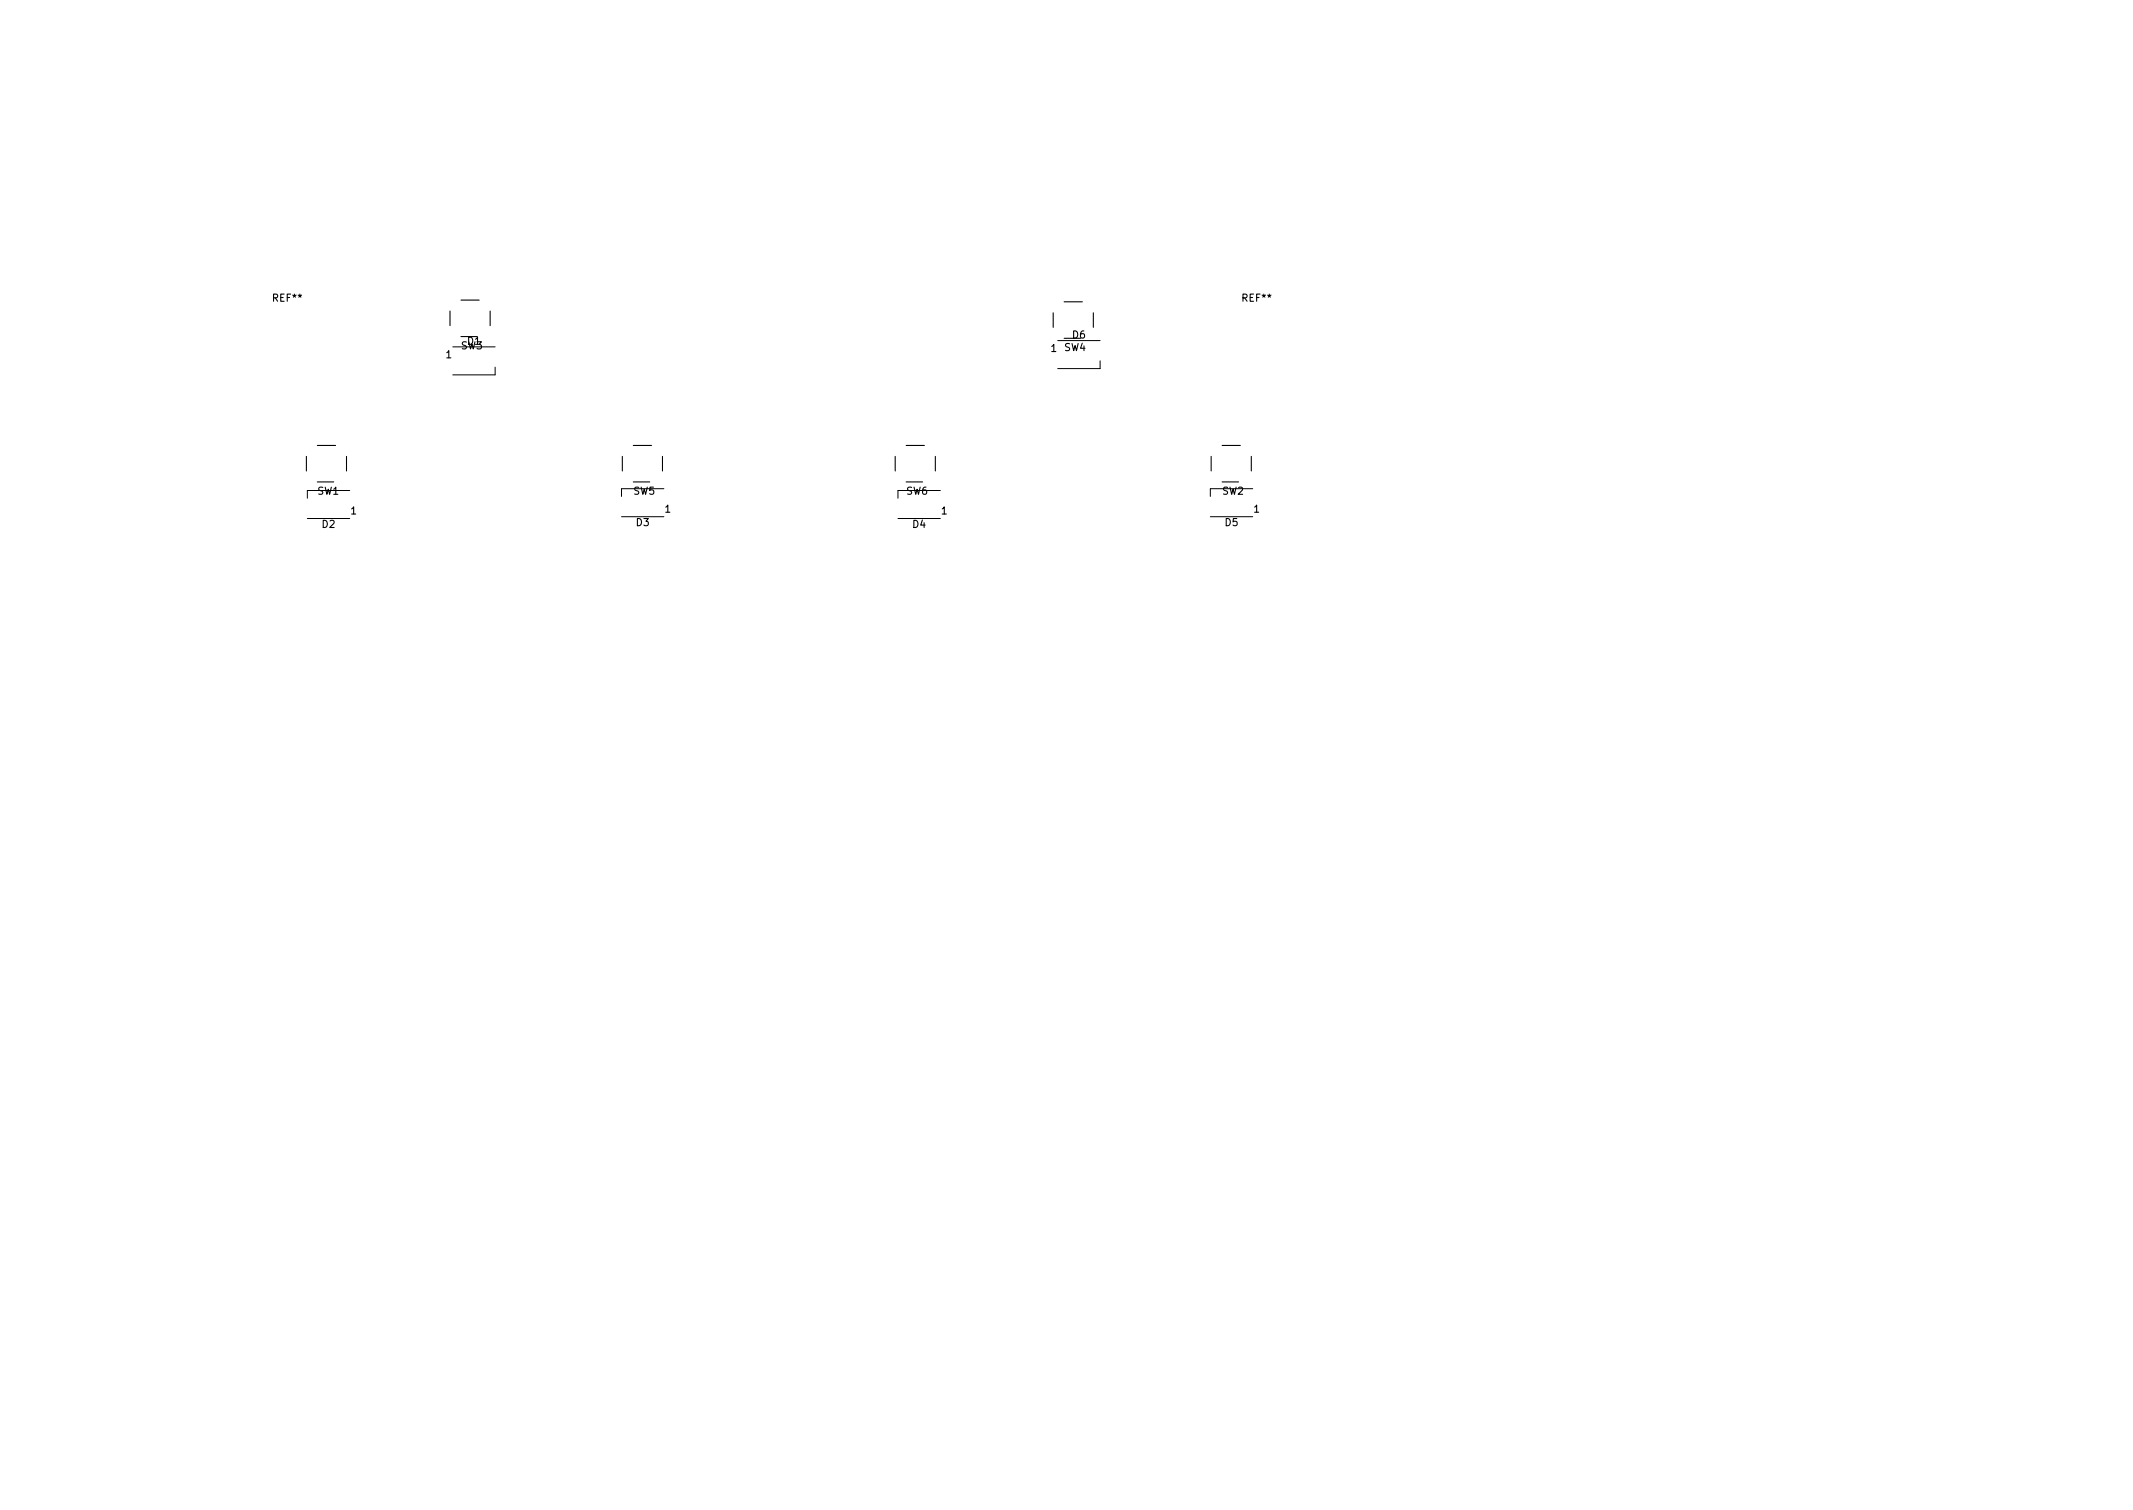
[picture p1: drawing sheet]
<svg xmlns="http://www.w3.org/2000/svg" width="297mm" height="210mm" viewBox="0 0 297 210" stroke-linecap="round" stroke-linejoin="round" font-family="sans-serif">
<defs><g id="words">
<g font-size="1.4">
<text x="38.1" y="42">REF**</text>
<text x="173.1" y="42">REF**</text>
<text x="65.1" y="48">D1</text>
<text x="149.4" y="47.1">D6</text>
<text x="62.1" y="49.9">1</text>
<text x="64.2" y="48.6">SW3</text>
<text x="146.4" y="49">1</text>
<text x="148.2" y="48.9">SW4</text>
<text x="44.2" y="68.9">SW1</text>
<text x="48.9" y="71.6">1</text>
<text x="88.2" y="68.9">SW5</text>
<text x="92.6" y="71.4">1</text>
<text x="126.2" y="68.9">SW6</text>
<text x="131.1" y="71.6">1</text>
<text x="170.2" y="68.9">SW2</text>
<text x="174.6" y="71.4">1</text>
<text x="44.9" y="73.5">D2</text>
<text x="88.6" y="73.2">D3</text>
<text x="127.1" y="73.5">D4</text>
<text x="170.6" y="73.2">D5</text>
</g>
</g></defs>
<path d="M63 48.3h6M69 51.1v1.1h-6M147.3 47.4h5.9M153.2 50.2v1.1h-5.9M42.8 72.2h5.9M48.7 68.3h-5.9v1.1M86.5 71.9h5.9M92.4 68h-5.9v1.1M125.1 72.2h5.8M130.9 68.3h-5.8v1.1M168.6 71.9h5.8M174.4 68h-5.8v1.1" fill="none" stroke="#000" stroke-width=".14"/>
<g fill="none" stroke="#000" stroke-width=".15">
<path d="M62.7 43.3v2M64.2 41.8h2.5M64.2 46.9h2.3M68.3 43.3v2M146.7 43.6v2M148.2 47.1h2.3M148.2 42h2.5M152.3 43.6v2M42.7 63.6v2M44.2 62h2.5M44.2 67.1h2.3M48.3 63.6v2"/>
<path d="M86.7 63.6v2M88.2 62h2.5M88.2 67.1h2.3M92.3 63.6v2M124.7 63.6v2M126.2 62h2.5M126.2 67.1h2.3M130.3 63.6v2M168.7 63.6v2M170.2 62h2.5M170.2 67.1h2.3M174.3 63.6v2"/>
</g>
<use href="#words"/>
</svg>
